VERSION 5.8 ;
BUSBITCHARS "[]" ;
DIVIDERCHAR "/" ;
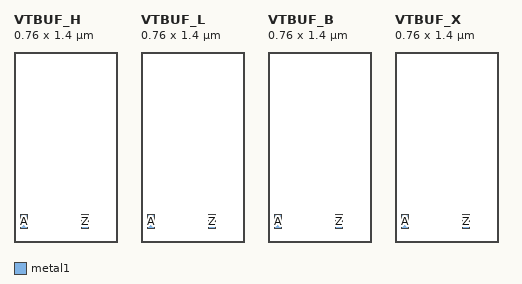
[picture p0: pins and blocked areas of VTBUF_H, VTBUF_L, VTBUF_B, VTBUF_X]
MACRO VTBUF_H
 CLASS CORE ; ORIGIN 0 0 ; SIZE 0.76 BY 1.4 ;
 SYMMETRY X Y ; SITE FreePDK45_38x28_10R_NP_162NW_34O ;
 PIN A
  DIRECTION INPUT ; USE SIGNAL ;
  PORT
   LAYER metal1 ; RECT 0.05 0.1 0.1 0.2 ;
  END
 END A
 PIN Z
  DIRECTION OUTPUT ; USE SIGNAL ;
  PORT
   LAYER metal1 ; RECT 0.5 0.1 0.55 0.2 ;
  END
 END Z
END VTBUF_H
MACRO VTBUF_L
 CLASS CORE ; ORIGIN 0 0 ; SIZE 0.76 BY 1.4 ;
 SYMMETRY X Y ; SITE FreePDK45_38x28_10R_NP_162NW_34O ;
 PIN A
  DIRECTION INPUT ; USE SIGNAL ;
  PORT
   LAYER metal1 ; RECT 0.05 0.1 0.1 0.2 ;
  END
 END A
 PIN Z
  DIRECTION OUTPUT ; USE SIGNAL ;
  PORT
   LAYER metal1 ; RECT 0.5 0.1 0.55 0.2 ;
  END
 END Z
END VTBUF_L
MACRO VTBUF_B
 CLASS CORE ; ORIGIN 0 0 ; SIZE 0.76 BY 1.4 ;
 SYMMETRY X Y ; SITE FreePDK45_38x28_10R_NP_162NW_34O ;
 PIN A
  DIRECTION INPUT ; USE SIGNAL ;
  PORT
   LAYER metal1 ; RECT 0.05 0.1 0.1 0.2 ;
  END
 END A
 PIN Z
  DIRECTION OUTPUT ; USE SIGNAL ;
  PORT
   LAYER metal1 ; RECT 0.5 0.1 0.55 0.2 ;
  END
 END Z
END VTBUF_B
MACRO VTBUF_X
 CLASS CORE ; ORIGIN 0 0 ; SIZE 0.76 BY 1.4 ;
 SYMMETRY X Y ; SITE FreePDK45_38x28_10R_NP_162NW_34O ;
 PIN A
  DIRECTION INPUT ; USE SIGNAL ;
  PORT
   LAYER metal1 ; RECT 0.05 0.1 0.1 0.2 ;
  END
 END A
 PIN Z
  DIRECTION OUTPUT ; USE SIGNAL ;
  PORT
   LAYER metal1 ; RECT 0.5 0.1 0.55 0.2 ;
  END
 END Z
END VTBUF_X
END LIBRARY
